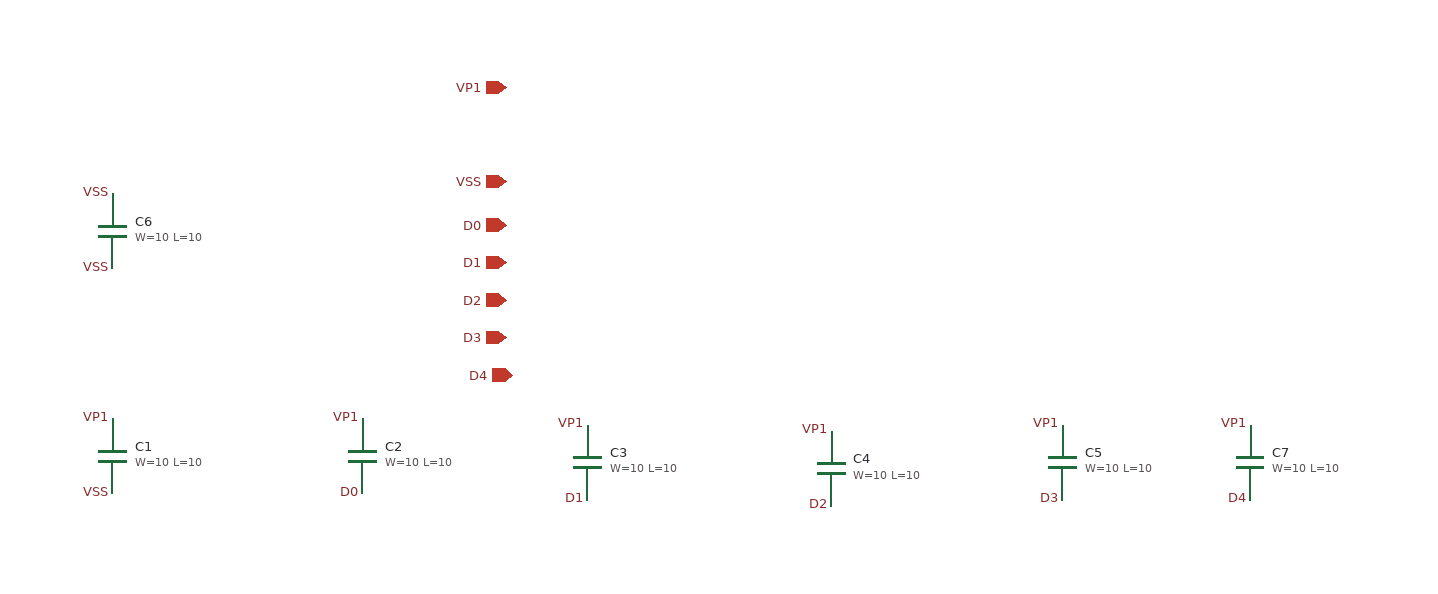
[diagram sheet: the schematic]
v {xschem version=3.1.0 file_version=1.2
}
G {}
K {}
V {}
S {}
E {}
C {sky130_fd_pr/cap_mim_m3_1.sym} 460 -850 0 0 {name=C1 model=cap_mim_m3_1 W=10 L=10 MF=1 spiceprefix=X}
C {sky130_fd_pr/cap_mim_m3_1.sym} 660 -850 0 0 {name=C2 model=cap_mim_m3_1 W=10 L=10 MF=1 spiceprefix=X}
C {devices/lab_pin.sym} 460 -880 0 0 {name=p4 sig_type=std_logic lab=VP1}
C {devices/lab_pin.sym} 460 -820 3 0 {name=p5 sig_type=std_logic lab=VSS}
C {devices/lab_pin.sym} 660 -820 3 0 {name=p7 sig_type=std_logic lab=D0}
C {devices/ipin.sym} 775 -1070 0 0 {name=p11 lab=VSS}
C {devices/lab_pin.sym} 660 -880 0 0 {name=p1 sig_type=std_logic lab=VP1}
C {devices/ipin.sym} 775 -1035 0 0 {name=p19 lab=D0}
C {devices/ipin.sym} 775 -1145 0 0 {name=p6 lab=VP1}
C {sky130_fd_pr/cap_mim_m3_1.sym} 840 -845 0 0 {name=C3 model=cap_mim_m3_1 W=10 L=10 MF=2 spiceprefix=X}
C {devices/lab_pin.sym} 840 -815 3 0 {name=p9 sig_type=std_logic lab=D1}
C {devices/lab_pin.sym} 840 -875 0 0 {name=p2 sig_type=std_logic lab=VP1}
C {devices/ipin.sym} 775 -1005 0 0 {name=p3 lab=D1}
C {sky130_fd_pr/cap_mim_m3_1.sym} 1035 -840 0 0 {name=C4 model=cap_mim_m3_1 W=10 L=10 MF=4 spiceprefix=X}
C {devices/lab_pin.sym} 1035 -810 3 0 {name=p10 sig_type=std_logic lab=D2}
C {devices/lab_pin.sym} 1035 -870 0 0 {name=p8 sig_type=std_logic lab=VP1}
C {devices/ipin.sym} 775 -975 0 0 {name=p12 lab=D2}
C {sky130_fd_pr/cap_mim_m3_1.sym} 1220 -845 0 0 {name=C5 model=cap_mim_m3_1 W=10 L=10 MF=8 spiceprefix=X}
C {devices/lab_pin.sym} 1220 -815 3 0 {name=p48 sig_type=std_logic lab=D3}
C {devices/lab_pin.sym} 1220 -875 0 0 {name=p13 sig_type=std_logic lab=VP1}
C {devices/ipin.sym} 775 -945 0 0 {name=p14 lab=D3}
C {sky130_fd_pr/cap_mim_m3_1.sym} 1370 -845 0 0 {name=C7 model=cap_mim_m3_1 W=10 L=10 MF=16 spiceprefix=X}
C {devices/lab_pin.sym} 1370 -815 3 0 {name=p72 sig_type=std_logic lab=D4}
C {devices/lab_pin.sym} 1370 -875 0 0 {name=p15 sig_type=std_logic lab=VP1}
C {devices/ipin.sym} 780 -915 0 0 {name=p16 lab=D4}
C {sky130_fd_pr/cap_mim_m3_1.sym} 460 -1030 0 0 {name=C6 model=cap_mim_m3_1 W=10 L=10 MF=32 spiceprefix=X}
C {devices/lab_pin.sym} 460 -1000 3 0 {name=p18 sig_type=std_logic lab=VSS}
C {devices/lab_pin.sym} 460 -1060 0 0 {name=p17 sig_type=std_logic lab=VSS}
